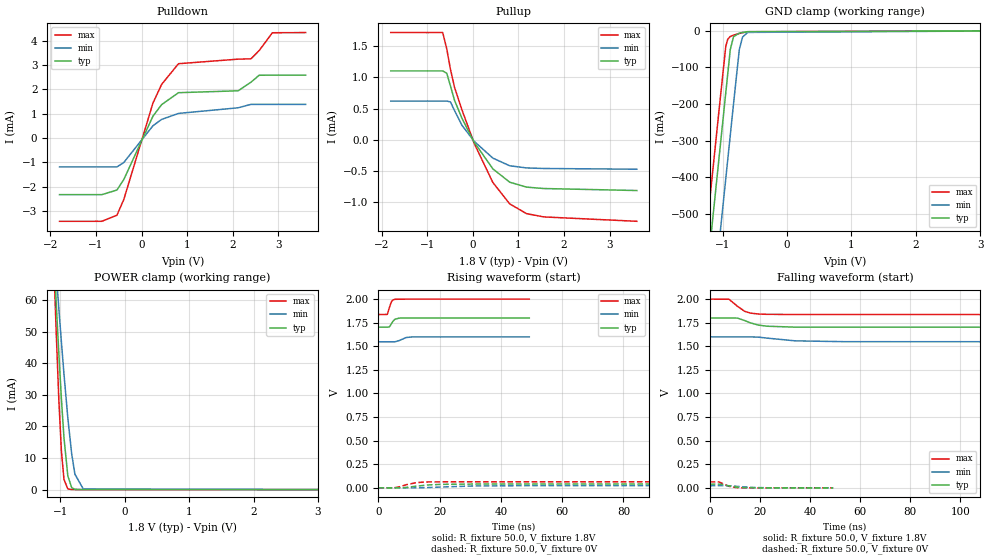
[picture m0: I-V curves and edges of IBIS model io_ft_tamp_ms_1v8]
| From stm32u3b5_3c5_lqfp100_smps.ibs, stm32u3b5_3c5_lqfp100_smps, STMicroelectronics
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[Model]   io_ft_tamp_ms_1v8
Model_type I/O
Polarity   Non-Inverting
Enable   Active-Low
| CAP_THRESHOLD on pad IOFT is "UDTCAPC" :
| Rising=30.0% of vddios   Falling=70.0% of vddios
| C_comp min and max val. don't necessarily correlate with the min and max pvt
| but are the smallest and greatest pad capacitance found.
| var   typ   min   max
C_comp   2.71729pF  2.71525pF  2.74582pF
|C_comp_pullup   1.48101pF  1.51704pF  1.63209pF
|C_comp_pulldown   1.23627pF  1.19820pF  1.11374pF
Vinl = 800.0mV
Vinh = 1.0V
Vmeas = 900.0mV   | Reference voltage for timing measurements
Cref  = 50.0pF   | Timing specification test load capacitance value
Rref  = 1.0MOhm   | Timing specification test load resistance value
Vref  = 990.0mV   | Timing specification test load voltage
[Model Spec]
| TIME_THRESHOLD on pin ZIV11 is "CMOS" :
| Rising=50.0% of vdd   Falling=50.0% of vdd
Vinl 694.50000mV 619.50000mV 778.50000mV
Vinh 1.08350V 957.50000mV 1.18750V
| variable   typ   min   max
[Temperature Range] 25.0 130.0 -40.0
| variable   typ   min   max
[Voltage Range] 1.8V 1.6V 2.0V
| variable   typ   min   max
[POWER Clamp Reference] 1.8V 1.6V 2.0V
| variable   typ   min   max
[GND Clamp Reference] 0V 0V 0V
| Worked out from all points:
|   slope of the pulldown table from 0 to 0.27 V, typ, clamps not added: 284 ohm
|   slope of the pullup table from 0 to 0.27 V, typ, clamps not added: 866 ohm
|   GND clamp passes 1 mA (typ) near -0.53 V on its own axis
|   POWER clamp passes 1 mA (typ) near -0.83 V on its own axis
|   rising waveform, R_fixture 50.0, V_fixture 1.8V: 20-80 % time 1.24ns typ, 2.05ns min, 929ps max; typ from 1.7 V to 1.8 V
|   falling waveform, R_fixture 50.0, V_fixture 1.8V: 20-80 % time 6.93ns typ, 11.6ns min, 4.78ns max; typ from 1.8 V to 1.7 V
[POWER Clamp]
-1.8V     399.1mA    292.1mA    557.7mA
-1.09V    71.2mA     76.8mA     67.14mA
-1.08V    67.05mA    73.98mA    61.2mA
-1.06V    58.89mA    68.38mA    49.67mA
-1.02V    43.22mA    57.4mA     28.67mA
-980mV    28.81mA    46.77mA    12.28mA
-940mV    16.45mA    36.61mA    3.257mA
-880mV    4.35mA     22.67mA    225.4uA
-820mV    610.4uA    11.29mA    13uA
-770mV    97.5uA     4.87mA     1.193uA
-640mV    753.5nA    196uA      2.462nA
3.6V      0A         0A         0A
[GND Clamp]
-1.8V     -1.614A    -1.849A    -1.484A
-1.3V     -764.3mA   -998.7mA   -634.2mA
-1.24V    -662.3mA   -896.7mA   -532.2mA
-1.05V    -339.3mA   -573.7mA   -209.2mA
-950mV    -169.3mA   -403.7mA   -42.69mA
-920mV    -118.3mA   -352.7mA   -23.09mA
-880mV    -51.11mA   -284.7mA   -15.46mA
-830mV    -16.2mA    -199.7mA   -11.8mA
-740mV    -6.183mA   -50.96mA   -7.241mA
-690mV    -4.389mA   -17.19mA   -5.148mA
-610mV    -2.335mA   -4.282mA   -2.511mA
3.6V      1.047nA    154.4nA    370.3pA
| variable   typ   min   max
[Pullup Reference] 1.8V 1.6V 2.0V
| variable   typ   min   max
[Pulldown Reference] 0V 0V 0V
[Pullup]
-1.8V     1.102mA    619.1uA    1.716mA
-660mV    1.102mA    619.1uA    1.716mA
-570mV    1.063mA    619.1uA    1.45mA
-490mV    862uA      605.5uA    1.128mA
-400mV    629.9uA    466.3uA    837.4uA
-240mV    346.7uA    234.5uA    482.5uA
30mV      -39.39uA   -25.35uA   -56.88uA
440mV     -465.7uA   -294.1uA   -684.5uA
810mV     -680.3uA   -417.2uA   -1.027mA
1.18V     -758.6uA   -451.3uA   -1.184mA
1.56V     -781.3uA   -460.5uA   -1.236mA
3.6V      -813.2uA   -472.1uA   -1.306mA
[Pulldown]
-1.8V     -2.333mA   -1.19mA    -3.431mA
-870mV    -2.333mA   -1.19mA    -3.431mA
-540mV    -2.142mA   -1.19mA    -3.179mA
-390mV    -1.711mA   -1.009mA   -2.535mA
250mV     900.6uA    504.7uA    1.44mA
440mV     1.376mA    767.1uA    2.21mA
810mV     1.868mA    1.014mA    3.062mA
2.12V     1.946mA    1.246mA    3.25mA
2.4V      2.301mA    1.387mA    3.263mA
2.58V     2.586mA    1.387mA    3.604mA
2.87V     2.592mA    1.387mA    4.337mA
3.6V      2.592mA    1.387mA    4.345mA
[Ramp]
dV/dt_r 23.67206mV/6.68875ns 13.82659mV/12.07137ns 37.88704mV/4.28139ns
dV/dt_f 58.29452mV/6.92871ns 31.0141mV/11.42989ns 97.50835mV/4.75345ns
R_load = 50.0
| Removed startup time: 0s 0s 0s  .
| Removed end time: 49.25ns.
[Rising Waveform]
R_fixture   = 50.0
V_fixture   = 1.8V
V_fixture_min = 1.6V
V_fixture_max = 2.0V
0s        1.703V     1.548V     1.837V
2.9ns     1.703V     1.548V     1.838V
3.55ns    1.705V     1.548V     1.908V
4.2ns     1.737V     1.548V     1.969V
4.7ns     1.763V     1.548V     1.991V
5.4ns     1.787V     1.548V     1.998V
6.8ns     1.799V     1.561V     1.999V
9.05ns    1.8V       1.593V     2V
11.05ns   1.8V       1.599V     2V
49.25ns   1.8V       1.6V       2V
| Removed startup time: 0s 0s 0s  .
| Removed end time: 499.2ns.
[Falling Waveform]
R_fixture   = 50.0
V_fixture   = 1.8V
V_fixture_min = 1.6V
V_fixture_max = 2.0V
0s        1.8V       1.6V       2V
7.7ns     1.8V       1.6V       1.999V
11.1ns    1.799V     1.6V       1.924V
13.95ns   1.773V     1.6V       1.871V
16.2ns    1.749V     1.6V       1.852V
19.45ns   1.725V     1.597V     1.842V
22.8ns    1.713V     1.587V     1.839V
34.05ns   1.703V     1.558V     1.837V
54ns      1.703V     1.549V     1.837V
499.2ns   1.703V     1.548V     1.837V
| Removed startup time: 0s 0s 0s  .
| Removed end time: 499.25ns.
[Rising Waveform]
R_fixture   = 50.0
V_fixture   = 0V
V_fixture_min = 0V
V_fixture_max = 0V
0s        14.15nV    218.7nV    13.56nV
5.05ns    -936.3uV   5.408uV    -381.5uV
7.05ns    -19.79uV   -535.7uV   11.8mV
9.15ns    4.026mV    -475uV     33.1mV
12.6ns    17.6mV     253.6uV    55.52mV
16.05ns   29.39mV    2.352mV    61.47mV
20.4ns    36.29mV    7.938mV    62.89mV
30.55ns   39.26mV    18.72mV    63.12mV
50.95ns   39.44mV    22.83mV    63.14mV
499.3ns   39.45mV    23.04mV    63.15mV
| Removed startup time: 0s 0s 0s  .
| Removed end time: 49.25ns.
[Falling Waveform]
R_fixture   = 50.0
V_fixture   = 0V
V_fixture_min = 0V
V_fixture_max = 0V
0s        39.45mV    23.05mV    63.15mV
3.7ns     39.43mV    23.05mV    62.91mV
4.4ns     38.93mV    23.05mV    54.69mV
7.7ns     20.47mV    22.47mV    16.1mV
9.65ns    11.33mV    18.23mV    6.136mV
11.45ns   5.932mV    14.54mV    1.106mV
15.1ns    746.6uV    7.982mV    200.6uV
18.1ns    226.3uV    4.009mV    73.51uV
23.15ns   77.96uV    937.3uV    12.74uV
49.25ns   206.1nV    9.817uV    1.821nV
